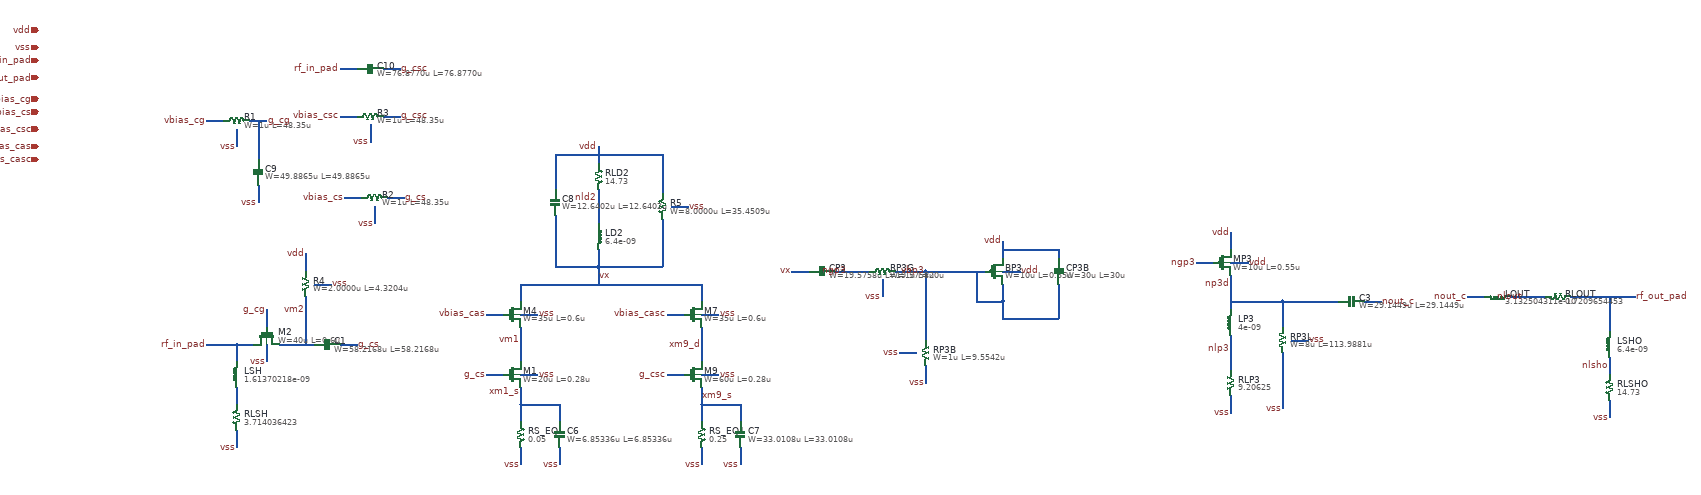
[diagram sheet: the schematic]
v {xschem version=3.4.8RC file_version=1.3}
G {}
K {}
V {}
S {}
F {}
E {}
N 690 -400 690 -360 {lab=#net1}
N 690 -500 690 -460 {lab=rf_in_pad}
N 690 -300 690 -260 {lab=vss}
N 790 -500 830 -500 {lab=vm2}
N 760 -580 760 -540 {lab=g_cg}
N 690 -500 730 -500 {lab=rf_in_pad}
N 760 -500 760 -460 {lab=vss}
N 620 -1020 660 -1020 {lab=vbias_cg}
N 720 -1020 760 -1020 {lab=g_cg}
N 690 -1000 690 -960 {lab=vss}
N 740 -870 740 -830 {lab=vss}
N 740 -970 740 -930 {lab=g_cg}
N 850 -610 850 -570 {lab=vm2}
N 850 -710 850 -670 {lab=vdd}
N 870 -640 910 -640 {lab=vss}
N 930 -500 970 -500 {lab=g_cs}
N 830 -500 870 -500 {lab=vm2}
N 940 -840 980 -840 {lab=vbias_cs}
N 1040 -840 1080 -840 {lab=g_cs}
N 1010 -820 1010 -780 {lab=vss}
N 1350 -500 1350 -460 {lab=vm1}
N 1270 -430 1310 -430 {lab=g_cs}
N 1350 -400 1350 -360 {lab=xm1_s}
N 1350 -430 1390 -430 {lab=vss}
N 1350 -360 1350 -320 {lab=xm1_s}
N 1350 -260 1350 -220 {lab=vss}
N 1440 -360 1440 -320 {lab=xm1_s}
N 1440 -260 1440 -220 {lab=vss}
N 1350 -640 1350 -600 {lab=vx}
N 1270 -570 1310 -570 {lab=vbias_cas}
N 1350 -540 1350 -500 {lab=vm1}
N 1350 -570 1390 -570 {lab=vss}
N 930 -1140 970 -1140 {lab=rf_in_pad}
N 1030 -1140 1070 -1140 {lab=g_csc}
N 930 -1030 970 -1030 {lab=vbias_csc}
N 1030 -1030 1070 -1030 {lab=g_csc}
N 1000 -1010 1000 -970 {lab=vss}
N 1770 -500 1770 -460 {lab=xm9_d}
N 1690 -430 1730 -430 {lab=g_csc}
N 1770 -400 1770 -360 {lab=xm9_s}
N 1770 -430 1810 -430 {lab=vss}
N 1770 -360 1770 -320 {lab=xm9_s}
N 1770 -260 1770 -220 {lab=vss}
N 1860 -360 1860 -320 {lab=xm9_s}
N 1860 -260 1860 -220 {lab=vss}
N 1770 -640 1770 -600 {lab=vx}
N 1690 -570 1730 -570 {lab=vbias_casc}
N 1770 -540 1770 -500 {lab=xm9_d}
N 1770 -570 1810 -570 {lab=vss}
N 1530 -820 1530 -780 {lab=nld2}
N 1530 -720 1530 -680 {lab=vx}
N 1530 -960 1530 -920 {lab=vdd}
N 1530 -860 1530 -820 {lab=nld2}
N 1680 -790 1680 -750 {lab=vx}
N 1680 -890 1680 -850 {lab=vdd}
N 1700 -820 1740 -820 {lab=vss}
N 1430 -900 1430 -860 {lab=vdd}
N 1430 -800 1430 -760 {lab=vx}
N 2080 -670 2120 -670 {lab=ngp3}
N 1980 -670 2020 -670 {lab=vx}
N 2120 -670 2160 -670 {lab=ngp3}
N 2220 -670 2260 -670 {lab=vbp3}
N 2190 -650 2190 -610 {lab=vss}
N 2470 -640 2470 -600 {lab=vbp3}
N 2390 -670 2430 -670 {lab=vbp3}
N 2470 -740 2470 -700 {lab=vdd}
N 2470 -670 2510 -670 {lab=vdd}
N 2290 -550 2290 -510 {lab=vbp3}
N 2290 -450 2290 -410 {lab=vss}
N 2230 -480 2270 -480 {lab=vss}
N 2470 -600 2470 -560 {lab=vbp3}
N 3000 -660 3000 -620 {lab=np3d}
N 2920 -690 2960 -690 {lab=ngp3}
N 3000 -760 3000 -720 {lab=vdd}
N 3000 -690 3040 -690 {lab=vdd}
N 3000 -520 3000 -480 {lab=nlp3}
N 3000 -620 3000 -580 {lab=np3d}
N 3000 -380 3000 -340 {lab=vss}
N 3000 -480 3000 -440 {lab=nlp3}
N 3120 -580 3120 -540 {lab=np3d}
N 3120 -480 3120 -440 {lab=vss}
N 3140 -510 3180 -510 {lab=vss}
N 3310 -600 3350 -600 {lab=nout_c}
N 3210 -600 3250 -600 {lab=np3d}
N 3650 -610 3690 -610 {lab=nlout}
N 3550 -610 3590 -610 {lab=nout_c}
N 3790 -610 3830 -610 {lab=rf_out_pad}
N 3690 -610 3730 -610 {lab=nlout}
N 3880 -470 3880 -430 {lab=nlsho}
N 3880 -370 3880 -330 {lab=vss}
N 740 -1020 740 -970 {lab=g_cg}
N 850 -570 850 -500 {lab=vm2}
N 1350 -360 1440 -360 {lab=xm1_s}
N 1770 -360 1860 -360 {lab=xm9_s}
N 3120 -600 3120 -580 {lab=np3d}
N 3000 -600 3120 -600 {lab=np3d}
N 3120 -440 3120 -350 {lab=vss}
N 3120 -600 3210 -600 {lab=np3d}
N 620 -500 690 -500 {lab=rf_in_pad}
N 1350 -640 1770 -640 {lab=vx}
N 1530 -680 1530 -640 {lab=vx}
N 1430 -940 1430 -900 {lab=vdd}
N 1430 -940 1530 -940 {lab=vdd}
N 1430 -760 1430 -680 {lab=vx}
N 1430 -680 1530 -680 {lab=vx}
N 1680 -940 1680 -890 {lab=vdd}
N 1530 -940 1680 -940 {lab=vdd}
N 1680 -750 1680 -680 {lab=vx}
N 1530 -680 1680 -680 {lab=vx}
N 2410 -600 2470 -600 {lab=vbp3}
N 2410 -670 2410 -600 {lab=vbp3}
N 2600 -720 2600 -700 {lab=vdd}
N 2470 -720 2600 -720 {lab=vdd}
N 2600 -640 2600 -560 {lab=vbp3}
N 2470 -560 2600 -560 {lab=vbp3}
N 2260 -670 2290 -670 {lab=vbp3}
N 2290 -670 2290 -550 {lab=vbp3}
N 2290 -670 2390 -670 {lab=vbp3}
N 3830 -610 3890 -610 {lab=rf_out_pad}
N 3880 -610 3880 -530 {lab=rf_out_pad}
N 3890 -610 3940 -610 {lab=rf_out_pad}
C {iopin.sym} 230 -1230 0 0 {name=p1 lab=vdd}
C {iopin.sym} 230 -1190 0 0 {name=p2 lab=vss}
C {iopin.sym} 230 -1160 0 0 {name=p3 lab=rf_in_pad}
C {iopin.sym} 230 -1120 0 0 {name=p4 lab=rf_out_pad}
C {iopin.sym} 230 -1070 0 0 {name=p5 lab=vbias_cg}
C {iopin.sym} 230 -1040 0 0 {name=p6 lab=vbias_cs}
C {iopin.sym} 230 -1000 0 0 {name=p7 lab=vbias_csc}
C {iopin.sym} 230 -960 0 0 {name=p8 lab=vbias_cas}
C {iopin.sym} 230 -930 0 0 {name=p9 lab=vbias_casc}
C {ind.sym} 690 -430 2 0 {name=LSH
m=1
value=1.61370218e-09
}
C {lab_pin.sym} 620 -500 0 0 {name=l11 sig_type=std_logic lab=rf_in_pad}
C {res.sym} 690 -330 2 0 {name=RLSH
value=3.714036423
m=1
}
C {lab_pin.sym} 690 -260 3 0 {name=l12 sig_type=std_logic lab=vss}
C {symbols/nfet_05v0.sym} 760 -520 1 0 {name=M2
L=0.6u
W=40u
nf=10
m=1
ad="'int((nf+1)/2) * W/nf * 0.18u'"
pd="'2*int((nf+1)/2) * (W/nf + 0.18u)'"
as="'int((nf+2)/2) * W/nf * 0.18u'"
ps="'2*int((nf+2)/2) * (W/nf + 0.18u)'"
nrd="'0.18u / W'"
nrs="'0.18u / W'"
sa=0
sb=0
sd=0
model=nfet_05v0
spiceprefix=X
}
C {lab_pin.sym} 760 -580 1 0 {name=l15 sig_type=std_logic lab=g_cg}
C {lab_pin.sym} 910 -640 2 0 {name=l17 sig_type=std_logic lab=vss}
C {symbols/ppolyf_u_1k.sym} 690 -1020 3 0 {name=R1
W=1u
L=48.35u
model=ppolyf_u_1k
spiceprefix=X
m=1
}
C {lab_pin.sym} 620 -1020 0 0 {name=l18 sig_type=std_logic lab=vbias_cg}
C {lab_pin.sym} 760 -1020 2 0 {name=l19 sig_type=std_logic lab=g_cg}
C {lab_pin.sym} 690 -960 3 0 {name=l20 sig_type=std_logic lab=vss}
C {symbols/cap_mim_2f0fF.sym} 740 -900 2 0 {name=C9
W=49.8865u
L=49.8865u
model=cap_mim_2f0_m4m5_noshield
spiceprefix=X
m=4
}
C {lab_pin.sym} 740 -830 3 0 {name=l21 sig_type=std_logic lab=vss}
C {symbols/ppolyf_u.sym} 850 -640 2 0 {name=R4
W=2.0000u
L=4.3204u
model=ppolyf_u
spiceprefix=X
m=1
}
C {lab_pin.sym} 850 -710 1 0 {name=l24 sig_type=std_logic lab=vdd}
C {lab_pin.sym} 760 -460 3 0 {name=l25 sig_type=std_logic lab=vss}
C {symbols/cap_mim_2f0fF.sym} 900 -500 1 0 {name=C1
W=58.2168u
L=58.2168u
model=cap_mim_2f0_m4m5_noshield
spiceprefix=X
m=1
}
C {lab_pin.sym} 970 -500 2 0 {name=l26 sig_type=std_logic lab=g_cs}
C {symbols/ppolyf_u_1k.sym} 1010 -840 3 0 {name=R2
W=1u
L=48.35u
model=ppolyf_u_1k
spiceprefix=X
m=1
}
C {lab_pin.sym} 940 -840 0 0 {name=l28 sig_type=std_logic lab=vbias_cs}
C {lab_pin.sym} 1080 -840 2 0 {name=l29 sig_type=std_logic lab=g_cs}
C {lab_pin.sym} 1010 -780 3 0 {name=l30 sig_type=std_logic lab=vss}
C {symbols/nfet_03v3.sym} 1330 -430 0 0 {name=M1
L=0.28u
W=20u
nf=10
m=2
ad="'int((nf+1)/2) * W/nf * 0.18u'"
pd="'2*int((nf+1)/2) * (W/nf + 0.18u)'"
as="'int((nf+2)/2) * W/nf * 0.18u'"
ps="'2*int((nf+2)/2) * (W/nf + 0.18u)'"
nrd="'0.18u / W'"
nrs="'0.18u / W'"
sa=0
sb=0
sd=0
model=nfet_03v3
spiceprefix=X
}
C {lab_pin.sym} 1270 -430 0 0 {name=l32 sig_type=std_logic lab=g_cs}
C {lab_pin.sym} 1350 -390 0 0 {name=l33 sig_type=std_logic lab=xm1_s}
C {lab_pin.sym} 1390 -430 2 0 {name=l34 sig_type=std_logic lab=vss}
C {res.sym} 1350 -290 0 0 {name=RS_EQ
value=0.05
m=1
}
C {lab_pin.sym} 1350 -220 3 0 {name=l36 sig_type=std_logic lab=vss}
C {symbols/cap_mim_2f0fF.sym} 1440 -290 0 0 {name=C6
W=6.85336u
L=6.85336u
model=cap_mim_2f0_m4m5_noshield
spiceprefix=X
m=1
}
C {lab_pin.sym} 1440 -220 3 0 {name=l38 sig_type=std_logic lab=vss}
C {symbols/nfet_05v0.sym} 1330 -570 0 0 {name=M4
L=0.6u
W=35u
nf=10
m=1
ad="'int((nf+1)/2) * W/nf * 0.18u'"
pd="'2*int((nf+1)/2) * (W/nf + 0.18u)'"
as="'int((nf+2)/2) * W/nf * 0.18u'"
ps="'2*int((nf+2)/2) * (W/nf + 0.18u)'"
nrd="'0.18u / W'"
nrs="'0.18u / W'"
sa=0
sb=0
sd=0
model=nfet_05v0
spiceprefix=X
}
C {lab_pin.sym} 1530 -660 2 0 {name=l39 sig_type=std_logic lab=vx}
C {lab_pin.sym} 1270 -570 0 0 {name=l40 sig_type=std_logic lab=vbias_cas}
C {lab_pin.sym} 1350 -510 0 0 {name=l41 sig_type=std_logic lab=vm1}
C {lab_pin.sym} 1390 -570 2 0 {name=l42 sig_type=std_logic lab=vss}
C {symbols/cap_mim_2f0fF.sym} 1000 -1140 3 0 {name=C10
W=76.8770u
L=76.8770u
model=cap_mim_2f0_m4m5_noshield
spiceprefix=X
m=1
}
C {lab_pin.sym} 930 -1140 0 0 {name=l43 sig_type=std_logic lab=rf_in_pad}
C {lab_pin.sym} 1070 -1140 2 0 {name=l44 sig_type=std_logic lab=g_csc}
C {symbols/ppolyf_u_1k.sym} 1000 -1030 3 0 {name=R3
W=1u
L=48.35u
model=ppolyf_u_1k
spiceprefix=X
m=1
}
C {lab_pin.sym} 930 -1030 0 0 {name=l45 sig_type=std_logic lab=vbias_csc}
C {lab_pin.sym} 1070 -1030 2 0 {name=l46 sig_type=std_logic lab=g_csc}
C {lab_pin.sym} 1000 -970 3 0 {name=l47 sig_type=std_logic lab=vss}
C {symbols/nfet_03v3.sym} 1750 -430 0 0 {name=M9
L=0.28u
W=60u
nf=4
m=8
ad="'int((nf+1)/2) * W/nf * 0.18u'"
pd="'2*int((nf+1)/2) * (W/nf + 0.18u)'"
as="'int((nf+2)/2) * W/nf * 0.18u'"
ps="'2*int((nf+2)/2) * (W/nf + 0.18u)'"
nrd="'0.18u / W'"
nrs="'0.18u / W'"
sa=0
sb=0
sd=0
model=nfet_03v3
spiceprefix=X
}
C {lab_pin.sym} 1690 -430 0 0 {name=l49 sig_type=std_logic lab=g_csc}
C {lab_pin.sym} 1770 -380 2 0 {name=l50 sig_type=std_logic lab=xm9_s}
C {lab_pin.sym} 1810 -430 2 0 {name=l51 sig_type=std_logic lab=vss}
C {res.sym} 1770 -290 0 0 {name=RS_EQ1
value=0.25
m=1
}
C {lab_pin.sym} 1770 -220 3 0 {name=l53 sig_type=std_logic lab=vss}
C {symbols/cap_mim_2f0fF.sym} 1860 -290 0 0 {name=C7
W=33.0108u
L=33.0108u
model=cap_mim_2f0_m4m5_noshield
spiceprefix=X
m=1
}
C {lab_pin.sym} 1860 -220 3 0 {name=l55 sig_type=std_logic lab=vss}
C {symbols/nfet_05v0.sym} 1750 -570 0 0 {name=M7
L=0.6u
W=35u
nf=10
m=4
ad="'int((nf+1)/2) * W/nf * 0.18u'"
pd="'2*int((nf+1)/2) * (W/nf + 0.18u)'"
as="'int((nf+2)/2) * W/nf * 0.18u'"
ps="'2*int((nf+2)/2) * (W/nf + 0.18u)'"
nrd="'0.18u / W'"
nrs="'0.18u / W'"
sa=0
sb=0
sd=0
model=nfet_05v0
spiceprefix=X
}
C {lab_pin.sym} 1690 -570 0 0 {name=l57 sig_type=std_logic lab=vbias_casc}
C {lab_pin.sym} 1770 -500 0 0 {name=l58 sig_type=std_logic lab=xm9_d}
C {lab_pin.sym} 1810 -570 2 0 {name=l59 sig_type=std_logic lab=vss}
C {ind.sym} 1530 -750 0 0 {name=LD2
m=1
value=6.4e-09
}
C {res.sym} 1530 -890 0 0 {name=RLD2
value=14.73
m=1
}
C {lab_pin.sym} 1530 -960 1 0 {name=l62 sig_type=std_logic lab=vdd}
C {lab_pin.sym} 1530 -840 0 0 {name=l63 sig_type=std_logic lab=nld2}
C {symbols/ppolyf_u.sym} 1680 -820 2 0 {name=R5
W=8.0000u
L=35.4509u
model=ppolyf_u
spiceprefix=X
m=1
}
C {lab_pin.sym} 1740 -820 2 0 {name=l66 sig_type=std_logic lab=vss}
C {symbols/cap_mim_2f0fF.sym} 1430 -830 0 1 {name=C8
W=12.6402u
L=12.6402u
model=cap_mim_2f0_m4m5_noshield
spiceprefix=X
m=1
}
C {symbols/cap_mim_2f0fF.sym} 2050 -670 1 0 {name=CP3
W=19.5758u
L=19.5758u
model=cap_mim_2f0_m4m5_noshield
spiceprefix=X
m=1
}
C {lab_pin.sym} 1980 -670 0 0 {name=l70 sig_type=std_logic lab=vx}
C {symbols/ppolyf_u_1k.sym} 2190 -670 3 0 {name=RP3G
W=1u
L=20u
model=ppolyf_u_1k
spiceprefix=X
m=1
}
C {lab_pin.sym} 2110 -670 1 0 {name=l71 sig_type=std_logic lab=ngp3}
C {lab_pin.sym} 2190 -610 3 0 {name=l73 sig_type=std_logic lab=vss}
C {symbols/pfet_06v0.sym} 2450 -670 0 0 {name=BP3
L=0.55u
W=10u
nf=4
m=1
ad="'int((nf+1)/2) * W/nf * 0.18u'"
pd="'2*int((nf+1)/2) * (W/nf + 0.18u)'"
as="'int((nf+2)/2) * W/nf * 0.18u'"
ps="'2*int((nf+2)/2) * (W/nf + 0.18u)'"
nrd="'0.18u / W'"
nrs="'0.18u / W'"
sa=0
sb=0
sd=0
model=pfet_06v0
spiceprefix=X
}
C {lab_pin.sym} 2290 -670 1 0 {name=l75 sig_type=std_logic lab=vbp3}
C {lab_pin.sym} 2470 -740 1 0 {name=l76 sig_type=std_logic lab=vdd}
C {lab_pin.sym} 2510 -670 2 0 {name=l77 sig_type=std_logic lab=vdd}
C {symbols/ppolyf_u_1k.sym} 2290 -480 0 0 {name=RP3B
W=1u
L=9.5542u
model=ppolyf_u_1k
spiceprefix=X
m=1
}
C {lab_pin.sym} 2290 -410 3 0 {name=l79 sig_type=std_logic lab=vss}
C {lab_pin.sym} 2230 -480 0 0 {name=l80 sig_type=std_logic lab=vss}
C {symbols/cap_mim_2f0fF.sym} 2600 -670 0 0 {name=CP3B
W=30u
L=30u
model=cap_mim_2f0_m4m5_noshield
spiceprefix=X
m=1
}
C {symbols/pfet_06v0.sym} 2980 -690 0 0 {name=MP3
L=0.55u
W=10u
nf=4
m=36
ad="'int((nf+1)/2) * W/nf * 0.18u'"
pd="'2*int((nf+1)/2) * (W/nf + 0.18u)'"
as="'int((nf+2)/2) * W/nf * 0.18u'"
ps="'2*int((nf+2)/2) * (W/nf + 0.18u)'"
nrd="'0.18u / W'"
nrs="'0.18u / W'"
sa=0
sb=0
sd=0
model=pfet_06v0
spiceprefix=X
}
C {lab_pin.sym} 3000 -640 0 0 {name=l83 sig_type=std_logic lab=np3d}
C {lab_pin.sym} 2920 -690 0 0 {name=l84 sig_type=std_logic lab=ngp3}
C {lab_pin.sym} 3000 -760 1 0 {name=l85 sig_type=std_logic lab=vdd}
C {lab_pin.sym} 3040 -690 2 0 {name=l86 sig_type=std_logic lab=vdd}
C {ind.sym} 3000 -550 2 0 {name=LP3
m=1
value=4e-09
}
C {lab_pin.sym} 3000 -490 0 0 {name=l87 sig_type=std_logic lab=nlp3}
C {res.sym} 3000 -410 2 0 {name=RLP3
value=9.20625
m=1
}
C {lab_pin.sym} 3000 -340 3 0 {name=l89 sig_type=std_logic lab=vss}
C {symbols/ppolyf_u.sym} 3120 -510 0 1 {name=RP3L
W=8u
L=113.9881u
model=ppolyf_u
spiceprefix=X
m=1
}
C {lab_pin.sym} 3120 -350 3 0 {name=l92 sig_type=std_logic lab=vss}
C {lab_pin.sym} 3180 -510 0 1 {name=l93 sig_type=std_logic lab=vss}
C {symbols/cap_mim_2f0fF.sym} 3280 -600 1 0 {name=C3
W=29.1449u
L=29.1449u
model=cap_mim_2f0_m4m5_noshield
spiceprefix=X
m=1
}
C {lab_pin.sym} 3350 -600 2 0 {name=l94 sig_type=std_logic lab=nout_c}
C {ind.sym} 3620 -610 1 0 {name=LOUT
m=1
value=3.132504311e-10
}
C {lab_pin.sym} 3680 -610 3 0 {name=l96 sig_type=std_logic lab=nlout}
C {lab_pin.sym} 3550 -610 0 0 {name=l97 sig_type=std_logic lab=nout_c}
C {res.sym} 3760 -610 1 0 {name=RLOUT
value=0.7209654453
m=1
}
C {lab_pin.sym} 3940 -610 2 0 {name=l98 sig_type=std_logic lab=rf_out_pad}
C {ind.sym} 3880 -500 2 0 {name=LSHO
m=1
value=6.4e-09
}
C {lab_pin.sym} 3880 -450 0 0 {name=l100 sig_type=std_logic lab=nlsho}
C {res.sym} 3880 -400 2 0 {name=RLSHO
value=14.73
m=1
}
C {lab_pin.sym} 3880 -330 3 0 {name=l102 sig_type=std_logic lab=vss}
C {lab_pin.sym} 850 -580 0 0 {name=l1 sig_type=std_logic lab=vm2}
